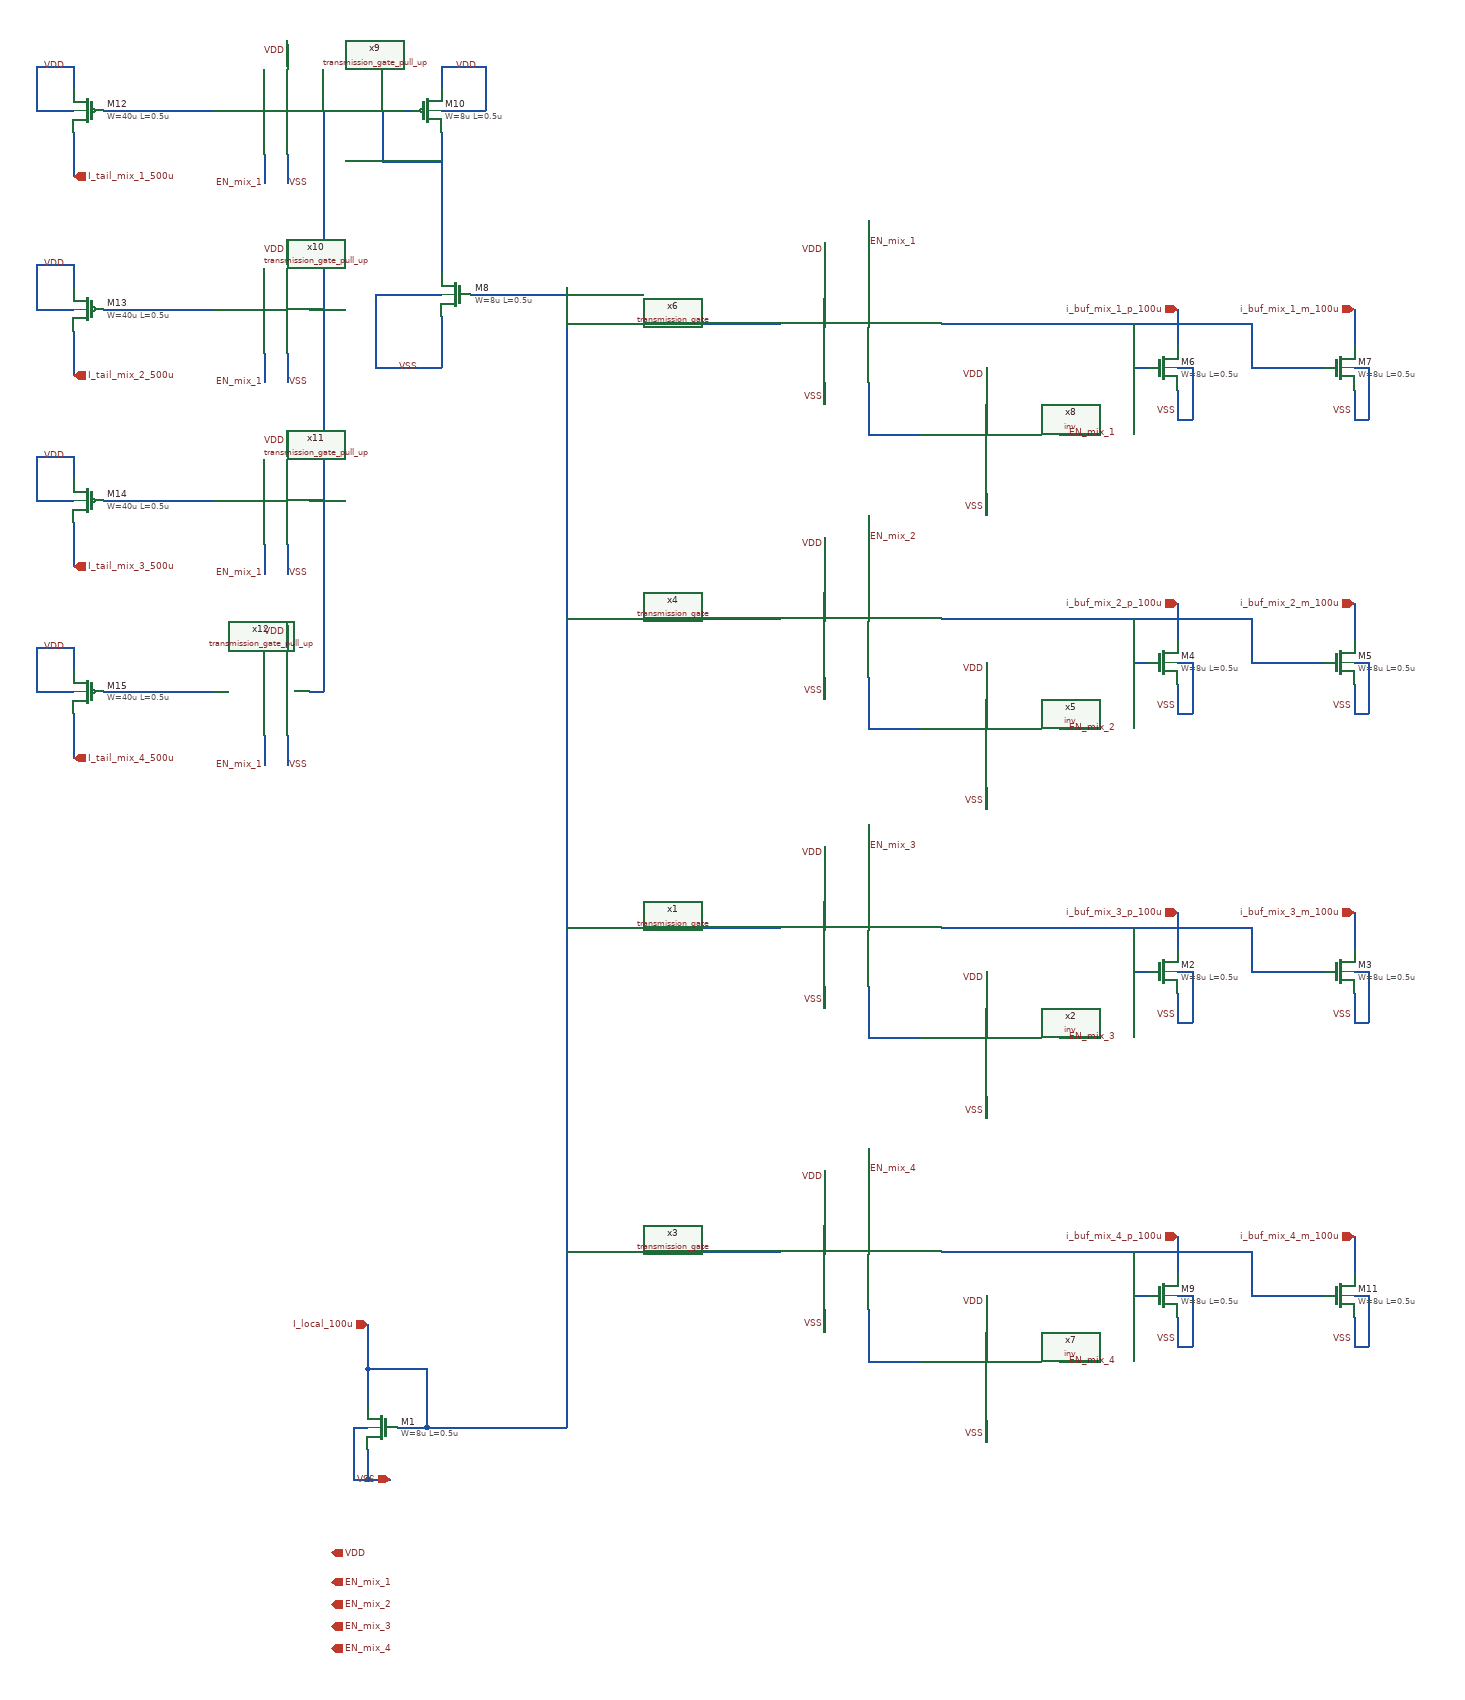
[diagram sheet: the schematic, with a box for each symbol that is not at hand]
v {xschem version=3.4.8RC file_version=1.3}
G {}
K {}
V {}
S {}
F {}
E {}
P 4 1 250 -690 {}
N 210 -510 210 -470 {lab=VSS}
N 210 -620 210 -570 {lab=I_local_100u}
N 210 -650 210 -620 {lab=I_local_100u}
N 210 -620 290 -620 {lab=I_local_100u}
N 290 -620 290 -540 {lab=I_local_100u}
N 250 -540 290 -540 {lab=I_local_100u}
N 190 -540 210 -540 {lab=VSS}
N 190 -540 190 -490 {lab=VSS}
N 190 -490 190 -470 {lab=VSS}
N 190 -470 210 -470 {lab=VSS}
N 290 -540 360 -540 {lab=I_local_100u}
N 210 -680 210 -650 {lab=I_local_100u}
N 210 -470 240 -470 {lab=VSS}
N 360 -540 460 -540 {lab=I_local_100u}
N 830 -890 830 -860 {lab=VDD}
N 830 -700 830 -670 {lab=VSS}
N 890 -920 890 -860 {lab=EN_mix_4}
N 890 -700 890 -660 {lab=#net1}
N 900 -630 960 -630 {lab=#net1}
N 1050 -550 1050 -520 {lab=VSS}
N 1050 -720 1050 -700 {lab=VDD}
N 1150 -630 1180 -630 {lab=EN_mix_4}
N 890 -630 900 -630 {lab=#net1}
N 890 -660 890 -630 {lab=#net1}
N 460 -540 480 -540 {lab=I_local_100u}
N 480 -1290 480 -540 {lab=I_local_100u}
N 480 -780 770 -780 {lab=I_local_100u}
N 1310 -690 1310 -650 {lab=VSS}
N 1310 -800 1310 -750 {lab=i_buf_mix_4_p_100u}
N 1310 -720 1330 -720 {lab=VSS}
N 1330 -720 1330 -650 {lab=VSS}
N 1310 -650 1330 -650 {lab=VSS}
N 1550 -690 1550 -650 {lab=VSS}
N 1550 -800 1550 -750 {lab=i_buf_mix_4_m_100u}
N 1550 -720 1570 -720 {lab=VSS}
N 1570 -720 1570 -650 {lab=VSS}
N 1550 -650 1570 -650 {lab=VSS}
N 1410 -780 1410 -720 {lab=#net2}
N 1410 -720 1420 -720 {lab=#net2}
N 1420 -720 1510 -720 {lab=#net2}
N 990 -780 1410 -780 {lab=#net2}
N 1250 -720 1270 -720 {lab=#net2}
N 1250 -780 1250 -720 {lab=#net2}
N 830 -1330 830 -1300 {lab=VDD}
N 830 -1140 830 -1110 {lab=VSS}
N 890 -1360 890 -1300 {lab=EN_mix_3}
N 890 -1140 890 -1100 {lab=#net3}
N 900 -1070 960 -1070 {lab=#net3}
N 1050 -990 1050 -960 {lab=VSS}
N 1050 -1160 1050 -1140 {lab=VDD}
N 1150 -1070 1180 -1070 {lab=EN_mix_3}
N 890 -1070 900 -1070 {lab=#net3}
N 890 -1100 890 -1070 {lab=#net3}
N 480 -1220 770 -1220 {lab=I_local_100u}
N 1310 -1130 1310 -1090 {lab=VSS}
N 1310 -1240 1310 -1190 {lab=i_buf_mix_3_p_100u}
N 1310 -1160 1330 -1160 {lab=VSS}
N 1330 -1160 1330 -1090 {lab=VSS}
N 1310 -1090 1330 -1090 {lab=VSS}
N 1550 -1130 1550 -1090 {lab=VSS}
N 1550 -1240 1550 -1190 {lab=i_buf_mix_3_m_100u}
N 1550 -1160 1570 -1160 {lab=VSS}
N 1570 -1160 1570 -1090 {lab=VSS}
N 1550 -1090 1570 -1090 {lab=VSS}
N 1410 -1220 1410 -1160 {lab=#net4}
N 1410 -1160 1420 -1160 {lab=#net4}
N 1420 -1160 1510 -1160 {lab=#net4}
N 990 -1220 1410 -1220 {lab=#net4}
N 1250 -1160 1270 -1160 {lab=#net4}
N 1250 -1220 1250 -1160 {lab=#net4}
N 830 -1750 830 -1720 {lab=VDD}
N 830 -1560 830 -1530 {lab=VSS}
N 890 -1780 890 -1720 {lab=EN_mix_2}
N 890 -1560 890 -1520 {lab=#net5}
N 900 -1490 960 -1490 {lab=#net5}
N 1050 -1410 1050 -1380 {lab=VSS}
N 1050 -1580 1050 -1560 {lab=VDD}
N 1150 -1490 1180 -1490 {lab=EN_mix_2}
N 890 -1490 900 -1490 {lab=#net5}
N 890 -1520 890 -1490 {lab=#net5}
N 480 -1640 770 -1640 {lab=I_local_100u}
N 1310 -1550 1310 -1510 {lab=VSS}
N 1310 -1660 1310 -1610 {lab=i_buf_mix_2_p_100u}
N 1310 -1580 1330 -1580 {lab=VSS}
N 1330 -1580 1330 -1510 {lab=VSS}
N 1310 -1510 1330 -1510 {lab=VSS}
N 1550 -1550 1550 -1510 {lab=VSS}
N 1550 -1660 1550 -1610 {lab=i_buf_mix_2_m_100u}
N 1550 -1580 1570 -1580 {lab=VSS}
N 1570 -1580 1570 -1510 {lab=VSS}
N 1550 -1510 1570 -1510 {lab=VSS}
N 1410 -1640 1410 -1580 {lab=#net6}
N 1410 -1580 1420 -1580 {lab=#net6}
N 1420 -1580 1510 -1580 {lab=#net6}
N 990 -1640 1410 -1640 {lab=#net6}
N 1250 -1580 1270 -1580 {lab=#net6}
N 1250 -1640 1250 -1580 {lab=#net6}
N 480 -2090 480 -1290 {lab=I_local_100u}
N 830 -2150 830 -2120 {lab=VDD}
N 830 -1960 830 -1930 {lab=VSS}
N 890 -2180 890 -2120 {lab=EN_mix_1}
N 890 -1960 890 -1920 {lab=#net7}
N 900 -1890 960 -1890 {lab=#net7}
N 1050 -1810 1050 -1780 {lab=VSS}
N 1050 -1980 1050 -1960 {lab=VDD}
N 1150 -1890 1180 -1890 {lab=EN_mix_1}
N 890 -1890 900 -1890 {lab=#net7}
N 890 -1920 890 -1890 {lab=#net7}
N 480 -2040 770 -2040 {lab=I_local_100u}
N 1310 -1950 1310 -1910 {lab=VSS}
N 1310 -2060 1310 -2010 {lab=i_buf_mix_1_p_100u}
N 1310 -1980 1330 -1980 {lab=VSS}
N 1330 -1980 1330 -1910 {lab=VSS}
N 1310 -1910 1330 -1910 {lab=VSS}
N 1550 -1950 1550 -1910 {lab=VSS}
N 1550 -2060 1550 -2010 {lab=i_buf_mix_1_m_100u}
N 1550 -1980 1570 -1980 {lab=VSS}
N 1570 -1980 1570 -1910 {lab=VSS}
N 1550 -1910 1570 -1910 {lab=VSS}
N 1410 -2040 1410 -1980 {lab=#net8}
N 1410 -1980 1420 -1980 {lab=#net8}
N 1420 -1980 1510 -1980 {lab=#net8}
N 990 -2040 1410 -2040 {lab=#net8}
N 1250 -1980 1270 -1980 {lab=#net8}
N 1250 -2040 1250 -1980 {lab=#net8}
N 350 -2080 480 -2080 {lab=I_local_100u}
N 310 -2270 310 -2110 {lab=#net9}
N 310 -2050 310 -1980 {lab=VSS}
N 220 -1980 310 -1980 {lab=VSS}
N 220 -2080 220 -1980 {lab=VSS}
N 220 -2080 310 -2080 {lab=VSS}
N 310 -2300 310 -2270 {lab=#net9}
N 310 -2330 370 -2330 {lab=VDD}
N 370 -2390 370 -2330 {lab=VDD}
N 310 -2390 370 -2390 {lab=VDD}
N 310 -2390 310 -2360 {lab=VDD}
N 130 -2330 270 -2330 {lab=#net9}
N 230 -2330 230 -2260 {lab=#net9}
N 230 -2260 310 -2260 {lab=#net9}
N -190 -2390 -190 -2360 {lab=VDD}
N -240 -2330 -190 -2330 {lab=VDD}
N -240 -2390 -240 -2330 {lab=VDD}
N -240 -2390 -190 -2390 {lab=VDD}
N -190 -2300 -190 -2240 {lab=I_tail_mix_1_500u}
N 100 -2270 100 -2230 {lab=VSS}
N 100 -2420 100 -2390 {lab=VDD}
N 70 -2270 70 -2230 {lab=EN_mix_1}
N -150 -2330 0 -2330 {lab=#net10}
N -190 -2120 -190 -2090 {lab=VDD}
N -240 -2060 -190 -2060 {lab=VDD}
N -240 -2120 -240 -2060 {lab=VDD}
N -240 -2120 -190 -2120 {lab=VDD}
N -190 -2030 -190 -1970 {lab=I_tail_mix_2_500u}
N 100 -2000 100 -1960 {lab=VSS}
N 100 -2150 100 -2120 {lab=VDD}
N 70 -2000 70 -1960 {lab=EN_mix_1}
N -150 -2060 0 -2060 {lab=#net11}
N -190 -1860 -190 -1830 {lab=VDD}
N -240 -1800 -190 -1800 {lab=VDD}
N -240 -1860 -240 -1800 {lab=VDD}
N -240 -1860 -190 -1860 {lab=VDD}
N -190 -1770 -190 -1710 {lab=I_tail_mix_3_500u}
N 100 -1740 100 -1700 {lab=VSS}
N 100 -1890 100 -1860 {lab=VDD}
N 70 -1740 70 -1700 {lab=EN_mix_1}
N -150 -1800 0 -1800 {lab=#net12}
N -190 -1600 -190 -1570 {lab=VDD}
N -240 -1540 -190 -1540 {lab=VDD}
N -240 -1600 -240 -1540 {lab=VDD}
N -240 -1600 -190 -1600 {lab=VDD}
N -190 -1510 -190 -1450 {lab=I_tail_mix_1_500u}
N 100 -1480 100 -1440 {lab=VSS}
N 100 -1630 100 -1600 {lab=VDD}
N 70 -1480 70 -1440 {lab=EN_mix_1}
N -150 -1540 0 -1540 {lab=#net13}
N 130 -1540 150 -1540 {lab=#net9}
N 150 -2330 150 -1540 {lab=#net9}
N 130 -2060 150 -2060 {lab=#net9}
N 130 -1800 150 -1800 {lab=#net9}
C {title.sym} 160 -30 0 0 {name=l1 author="Lei Chen"}
C {symbols/nfet_03v3.sym} 230 -540 0 1 {name=M1
L=0.5u
W=8u
nf=2
m=1
ad="'int((nf+1)/2) * W/nf * 0.18u'"
pd="'2*int((nf+1)/2) * (W/nf + 0.18u)'"
as="'int((nf+2)/2) * W/nf * 0.18u'"
ps="'2*int((nf+2)/2) * (W/nf + 0.18u)'"
nrd="'0.18u / W'" nrs="'0.18u / W'"
sa=0 sb=0 sd=0
model=nfet_03v3
spiceprefix=X
}
C {iopin.sym} 210 -680 0 0 {name=p5 lab=I_local_100u}
C {iopin.sym} 240 -470 0 0 {name=p2 lab=VSS}
C {lab_wire.sym} 830 -680 0 0 {name=p20 sig_type=std_logic lab=VSS}
C {designs/digital/schematic/transmission_gate.sym} 890 -780 0 0 {name=x3}
C {lab_wire.sym} 830 -880 0 0 {name=p22 sig_type=std_logic lab=VDD}
C {digital/schematic/inv.sym} 1050 -640 0 1 {name=x7}
C {lab_wire.sym} 1160 -630 0 1 {name=p32 sig_type=std_logic lab=EN_mix_4}
C {lab_wire.sym} 1050 -710 0 0 {name=p33 sig_type=std_logic lab=VDD}
C {lab_wire.sym} 1050 -530 0 0 {name=p34 sig_type=std_logic lab=VSS}
C {lab_wire.sym} 890 -890 0 1 {name=p35 sig_type=std_logic lab=EN_mix_4}
C {iopin.sym} 160 -370 0 1 {name=p13 lab=VDD}
C {iopin.sym} 160 -330 0 1 {name=p16 lab=EN_mix_1}
C {iopin.sym} 160 -300 0 1 {name=p9 lab=EN_mix_2}
C {iopin.sym} 160 -270 0 1 {name=p11 lab=EN_mix_3}
C {iopin.sym} 160 -240 0 1 {name=p18 lab=EN_mix_4}
C {symbols/nfet_03v3.sym} 1290 -720 0 0 {name=M9
L=0.5u
W=8u
nf=10
m=1
ad="'int((nf+1)/2) * W/nf * 0.18u'"
pd="'2*int((nf+1)/2) * (W/nf + 0.18u)'"
as="'int((nf+2)/2) * W/nf * 0.18u'"
ps="'2*int((nf+2)/2) * (W/nf + 0.18u)'"
nrd="'0.18u / W'" nrs="'0.18u / W'"
sa=0 sb=0 sd=0
model=nfet_03v3
spiceprefix=X
}
C {lab_wire.sym} 1310 -660 0 0 {name=p47 sig_type=std_logic lab=VSS}
C {symbols/nfet_03v3.sym} 1530 -720 0 0 {name=M11
L=0.5u
W=8u
nf=10
m=1
ad="'int((nf+1)/2) * W/nf * 0.18u'"
pd="'2*int((nf+1)/2) * (W/nf + 0.18u)'"
as="'int((nf+2)/2) * W/nf * 0.18u'"
ps="'2*int((nf+2)/2) * (W/nf + 0.18u)'"
nrd="'0.18u / W'" nrs="'0.18u / W'"
sa=0 sb=0 sd=0
model=nfet_03v3
spiceprefix=X
}
C {lab_wire.sym} 1550 -660 0 0 {name=p48 sig_type=std_logic lab=VSS}
C {iopin.sym} 1310 -800 0 0 {name=p74 lab=i_buf_mix_4_p_100u}
C {iopin.sym} 1550 -800 0 0 {name=p75 lab=i_buf_mix_4_m_100u}
C {lab_wire.sym} 830 -1120 0 0 {name=p1 sig_type=std_logic lab=VSS}
C {designs/digital/schematic/transmission_gate.sym} 890 -1220 0 0 {name=x1}
C {lab_wire.sym} 830 -1320 0 0 {name=p3 sig_type=std_logic lab=VDD}
C {digital/schematic/inv.sym} 1050 -1080 0 1 {name=x2}
C {lab_wire.sym} 1160 -1070 0 1 {name=p4 sig_type=std_logic lab=EN_mix_3}
C {lab_wire.sym} 1050 -1150 0 0 {name=p6 sig_type=std_logic lab=VDD}
C {lab_wire.sym} 1050 -970 0 0 {name=p7 sig_type=std_logic lab=VSS}
C {lab_wire.sym} 890 -1330 0 1 {name=p8 sig_type=std_logic lab=EN_mix_3}
C {symbols/nfet_03v3.sym} 1290 -1160 0 0 {name=M2
L=0.5u
W=8u
nf=10
m=1
ad="'int((nf+1)/2) * W/nf * 0.18u'"
pd="'2*int((nf+1)/2) * (W/nf + 0.18u)'"
as="'int((nf+2)/2) * W/nf * 0.18u'"
ps="'2*int((nf+2)/2) * (W/nf + 0.18u)'"
nrd="'0.18u / W'" nrs="'0.18u / W'"
sa=0 sb=0 sd=0
model=nfet_03v3
spiceprefix=X
}
C {lab_wire.sym} 1310 -1100 0 0 {name=p10 sig_type=std_logic lab=VSS}
C {symbols/nfet_03v3.sym} 1530 -1160 0 0 {name=M3
L=0.5u
W=8u
nf=10
m=1
ad="'int((nf+1)/2) * W/nf * 0.18u'"
pd="'2*int((nf+1)/2) * (W/nf + 0.18u)'"
as="'int((nf+2)/2) * W/nf * 0.18u'"
ps="'2*int((nf+2)/2) * (W/nf + 0.18u)'"
nrd="'0.18u / W'" nrs="'0.18u / W'"
sa=0 sb=0 sd=0
model=nfet_03v3
spiceprefix=X
}
C {lab_wire.sym} 1550 -1100 0 0 {name=p12 sig_type=std_logic lab=VSS}
C {iopin.sym} 1310 -1240 0 0 {name=p14 lab=i_buf_mix_3_p_100u}
C {iopin.sym} 1550 -1240 0 0 {name=p15 lab=i_buf_mix_3_m_100u}
C {lab_wire.sym} 830 -1540 0 0 {name=p17 sig_type=std_logic lab=VSS}
C {designs/digital/schematic/transmission_gate.sym} 890 -1640 0 0 {name=x4}
C {lab_wire.sym} 830 -1740 0 0 {name=p19 sig_type=std_logic lab=VDD}
C {digital/schematic/inv.sym} 1050 -1500 0 1 {name=x5}
C {lab_wire.sym} 1160 -1490 0 1 {name=p21 sig_type=std_logic lab=EN_mix_2}
C {lab_wire.sym} 1050 -1570 0 0 {name=p23 sig_type=std_logic lab=VDD}
C {lab_wire.sym} 1050 -1390 0 0 {name=p24 sig_type=std_logic lab=VSS}
C {lab_wire.sym} 890 -1750 0 1 {name=p25 sig_type=std_logic lab=EN_mix_2}
C {symbols/nfet_03v3.sym} 1290 -1580 0 0 {name=M4
L=0.5u
W=8u
nf=10
m=1
ad="'int((nf+1)/2) * W/nf * 0.18u'"
pd="'2*int((nf+1)/2) * (W/nf + 0.18u)'"
as="'int((nf+2)/2) * W/nf * 0.18u'"
ps="'2*int((nf+2)/2) * (W/nf + 0.18u)'"
nrd="'0.18u / W'" nrs="'0.18u / W'"
sa=0 sb=0 sd=0
model=nfet_03v3
spiceprefix=X
}
C {lab_wire.sym} 1310 -1520 0 0 {name=p26 sig_type=std_logic lab=VSS}
C {symbols/nfet_03v3.sym} 1530 -1580 0 0 {name=M5
L=0.5u
W=8u
nf=10
m=1
ad="'int((nf+1)/2) * W/nf * 0.18u'"
pd="'2*int((nf+1)/2) * (W/nf + 0.18u)'"
as="'int((nf+2)/2) * W/nf * 0.18u'"
ps="'2*int((nf+2)/2) * (W/nf + 0.18u)'"
nrd="'0.18u / W'" nrs="'0.18u / W'"
sa=0 sb=0 sd=0
model=nfet_03v3
spiceprefix=X
}
C {lab_wire.sym} 1550 -1520 0 0 {name=p27 sig_type=std_logic lab=VSS}
C {iopin.sym} 1310 -1660 0 0 {name=p28 lab=i_buf_mix_2_p_100u}
C {iopin.sym} 1550 -1660 0 0 {name=p29 lab=i_buf_mix_2_m_100u}
C {lab_wire.sym} 830 -1940 0 0 {name=p30 sig_type=std_logic lab=VSS}
C {designs/digital/schematic/transmission_gate.sym} 890 -2040 0 0 {name=x6}
C {lab_wire.sym} 830 -2140 0 0 {name=p31 sig_type=std_logic lab=VDD}
C {digital/schematic/inv.sym} 1050 -1900 0 1 {name=x8}
C {lab_wire.sym} 1160 -1890 0 1 {name=p36 sig_type=std_logic lab=EN_mix_1}
C {lab_wire.sym} 1050 -1970 0 0 {name=p37 sig_type=std_logic lab=VDD}
C {lab_wire.sym} 1050 -1790 0 0 {name=p38 sig_type=std_logic lab=VSS}
C {lab_wire.sym} 890 -2150 0 1 {name=p39 sig_type=std_logic lab=EN_mix_1}
C {symbols/nfet_03v3.sym} 1290 -1980 0 0 {name=M6
L=0.5u
W=8u
nf=10
m=1
ad="'int((nf+1)/2) * W/nf * 0.18u'"
pd="'2*int((nf+1)/2) * (W/nf + 0.18u)'"
as="'int((nf+2)/2) * W/nf * 0.18u'"
ps="'2*int((nf+2)/2) * (W/nf + 0.18u)'"
nrd="'0.18u / W'" nrs="'0.18u / W'"
sa=0 sb=0 sd=0
model=nfet_03v3
spiceprefix=X
}
C {lab_wire.sym} 1310 -1920 0 0 {name=p40 sig_type=std_logic lab=VSS}
C {symbols/nfet_03v3.sym} 1530 -1980 0 0 {name=M7
L=0.5u
W=8u
nf=10
m=1
ad="'int((nf+1)/2) * W/nf * 0.18u'"
pd="'2*int((nf+1)/2) * (W/nf + 0.18u)'"
as="'int((nf+2)/2) * W/nf * 0.18u'"
ps="'2*int((nf+2)/2) * (W/nf + 0.18u)'"
nrd="'0.18u / W'" nrs="'0.18u / W'"
sa=0 sb=0 sd=0
model=nfet_03v3
spiceprefix=X
}
C {lab_wire.sym} 1550 -1920 0 0 {name=p41 sig_type=std_logic lab=VSS}
C {iopin.sym} 1310 -2060 0 0 {name=p42 lab=i_buf_mix_1_p_100u}
C {iopin.sym} 1550 -2060 0 0 {name=p43 lab=i_buf_mix_1_m_100u}
C {symbols/nfet_03v3.sym} 330 -2080 0 1 {name=M8
L=0.5u
W=8u
nf=10
m=1
ad="'int((nf+1)/2) * W/nf * 0.18u'"
pd="'2*int((nf+1)/2) * (W/nf + 0.18u)'"
as="'int((nf+2)/2) * W/nf * 0.18u'"
ps="'2*int((nf+2)/2) * (W/nf + 0.18u)'"
nrd="'0.18u / W'" nrs="'0.18u / W'"
sa=0 sb=0 sd=0
model=nfet_03v3
spiceprefix=X
}
C {lab_wire.sym} 280 -1980 0 0 {name=p44 sig_type=std_logic lab=VSS}
C {symbols/pfet_03v3.sym} 290 -2330 0 0 {name=M10
L=0.5u
W=8u
nf=2
m=1
ad="'int((nf+1)/2) * W/nf * 0.18u'"
pd="'2*int((nf+1)/2) * (W/nf + 0.18u)'"
as="'int((nf+2)/2) * W/nf * 0.18u'"
ps="'2*int((nf+2)/2) * (W/nf + 0.18u)'"
nrd="'0.18u / W'" nrs="'0.18u / W'"
sa=0 sb=0 sd=0
model=pfet_03v3
spiceprefix=X
}
C {symbols/pfet_03v3.sym} -170 -2330 0 1 {name=M12
L=0.5u
W=40u
nf=10
m=1
ad="'int((nf+1)/2) * W/nf * 0.18u'"
pd="'2*int((nf+1)/2) * (W/nf + 0.18u)'"
as="'int((nf+2)/2) * W/nf * 0.18u'"
ps="'2*int((nf+2)/2) * (W/nf + 0.18u)'"
nrd="'0.18u / W'" nrs="'0.18u / W'"
sa=0 sb=0 sd=0
model=pfet_03v3
spiceprefix=X
}
C {digital/schematic/transmission_gate_pull_up.sym} 60 -2330 0 1 {name=x9}
C {lab_wire.sym} 360 -2390 0 0 {name=p45 sig_type=std_logic lab=VDD}
C {lab_wire.sym} 100 -2410 0 0 {name=p46 sig_type=std_logic lab=VDD}
C {lab_wire.sym} 100 -2230 0 1 {name=p49 sig_type=std_logic lab=VSS}
C {lab_wire.sym} 70 -2230 0 0 {name=p50 sig_type=std_logic lab=EN_mix_1}
C {lab_wire.sym} -200 -2390 0 0 {name=p51 sig_type=std_logic lab=VDD}
C {iopin.sym} -190 -2240 0 1 {name=p52 lab=I_tail_mix_1_500u}
C {symbols/pfet_03v3.sym} -170 -2060 0 1 {name=M13
L=0.5u
W=40u
nf=10
m=1
ad="'int((nf+1)/2) * W/nf * 0.18u'"
pd="'2*int((nf+1)/2) * (W/nf + 0.18u)'"
as="'int((nf+2)/2) * W/nf * 0.18u'"
ps="'2*int((nf+2)/2) * (W/nf + 0.18u)'"
nrd="'0.18u / W'" nrs="'0.18u / W'"
sa=0 sb=0 sd=0
model=pfet_03v3
spiceprefix=X
}
C {digital/schematic/transmission_gate_pull_up.sym} 60 -2060 0 1 {name=x10}
C {lab_wire.sym} 100 -2140 0 0 {name=p53 sig_type=std_logic lab=VDD}
C {lab_wire.sym} 100 -1960 0 1 {name=p54 sig_type=std_logic lab=VSS}
C {lab_wire.sym} 70 -1960 0 0 {name=p55 sig_type=std_logic lab=EN_mix_1}
C {lab_wire.sym} -200 -2120 0 0 {name=p56 sig_type=std_logic lab=VDD}
C {iopin.sym} -190 -1970 0 1 {name=p57 lab=I_tail_mix_2_500u}
C {symbols/pfet_03v3.sym} -170 -1800 0 1 {name=M14
L=0.5u
W=40u
nf=10
m=1
ad="'int((nf+1)/2) * W/nf * 0.18u'"
pd="'2*int((nf+1)/2) * (W/nf + 0.18u)'"
as="'int((nf+2)/2) * W/nf * 0.18u'"
ps="'2*int((nf+2)/2) * (W/nf + 0.18u)'"
nrd="'0.18u / W'" nrs="'0.18u / W'"
sa=0 sb=0 sd=0
model=pfet_03v3
spiceprefix=X
}
C {digital/schematic/transmission_gate_pull_up.sym} 60 -1800 0 1 {name=x11}
C {lab_wire.sym} 100 -1880 0 0 {name=p58 sig_type=std_logic lab=VDD}
C {lab_wire.sym} 100 -1700 0 1 {name=p59 sig_type=std_logic lab=VSS}
C {lab_wire.sym} 70 -1700 0 0 {name=p60 sig_type=std_logic lab=EN_mix_1}
C {lab_wire.sym} -200 -1860 0 0 {name=p61 sig_type=std_logic lab=VDD}
C {iopin.sym} -190 -1710 0 1 {name=p62 lab=I_tail_mix_3_500u}
C {symbols/pfet_03v3.sym} -170 -1540 0 1 {name=M15
L=0.5u
W=40u
nf=10
m=1
ad="'int((nf+1)/2) * W/nf * 0.18u'"
pd="'2*int((nf+1)/2) * (W/nf + 0.18u)'"
as="'int((nf+2)/2) * W/nf * 0.18u'"
ps="'2*int((nf+2)/2) * (W/nf + 0.18u)'"
nrd="'0.18u / W'" nrs="'0.18u / W'"
sa=0 sb=0 sd=0
model=pfet_03v3
spiceprefix=X
}
C {digital/schematic/transmission_gate_pull_up.sym} 60 -1540 0 1 {name=x12}
C {lab_wire.sym} 100 -1620 0 0 {name=p63 sig_type=std_logic lab=VDD}
C {lab_wire.sym} 100 -1440 0 1 {name=p64 sig_type=std_logic lab=VSS}
C {lab_wire.sym} 70 -1440 0 0 {name=p65 sig_type=std_logic lab=EN_mix_1}
C {lab_wire.sym} -200 -1600 0 0 {name=p66 sig_type=std_logic lab=VDD}
C {iopin.sym} -190 -1450 0 1 {name=p67 lab=I_tail_mix_4_500u}
